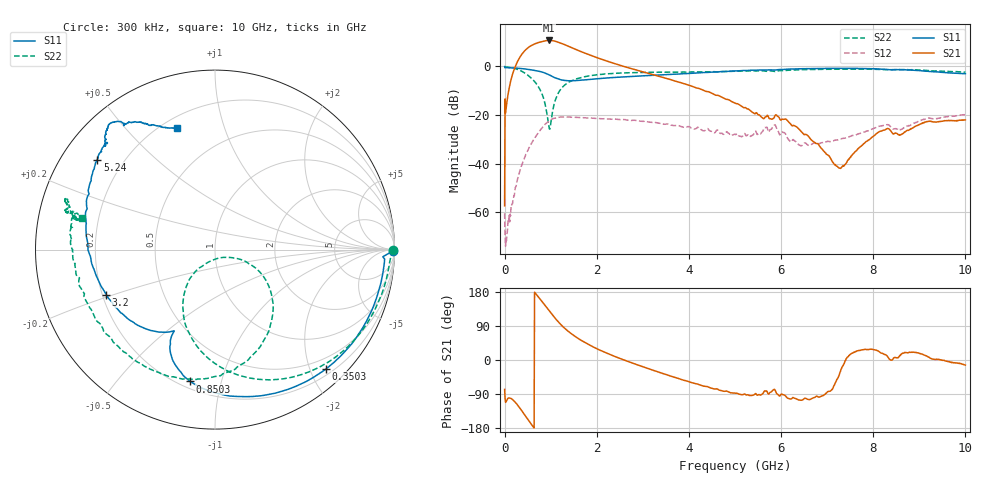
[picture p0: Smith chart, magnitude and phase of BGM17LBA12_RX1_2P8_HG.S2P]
!Agilent Technologies,E5071C,MY46316587,B.13.01
!Date: Fri Dec 08 10:52:52 2017
!Data & Calibration Information:
!Freq	S11:SOLT2(ON)	S21:SOLT2(ON)	S12:SOLT2(ON)	S22:SOLT2(ON)
!PortZ  Port1:50+j0  Port2:50+j0
!Above PortZ is port z conversion or system Z0 setting when saving the data.
!When reading, reference impedance value at option line is always used.
# Hz S dB R 50
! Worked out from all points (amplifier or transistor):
!   1001 points, 300 kHz to 10 GHz, reference 50 ohm
!   highest |S21| = 10.7 dB at 970.3 MHz (marker M1)
!   |S21| within 3 dB of that: 509.3 MHz to 1.459 GHz (950.1 MHz wide, 96.5 % of centre)
!   unconditionally stable (mu >= 1): start of sweep to end of sweep
!   at 1.66 GHz: K = 1.42, MAG = 9.7 dB, |S12| = -21.0 dB
!   at 5 GHz: K = 8.78, MAG = -6.0 dB, |S12| = -27.9 dB
!   at 10 GHz: K = 12.91, MAG = -15.2 dB, |S12| = -19.9 dB
!   lowest NFmin = 1.08 dB at 750 MHz
!   S11 on the Smith chart (normalised r, x): 300 kHz: open; 350.3 MHz: 0.30, -2.26; 850.3 MHz: 0.24, -0.80; 3.2 GHz: 0.22, -0.19; 5.24 GHz: 0.11, +0.34; 10 GHz: 0.26, +0.71
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300000  -0.06 -0.4  -57.37 -77.7  -60.44 90.1  -0.06 -0.2
6.02982e7  -0.50 -8.7  -13.28 -103.5  -67.89 118.9  -0.30 -11.4
2.102937e8  -0.63 -29.0  -1.13 -108.9  -53.25 155.8  -0.80 -37.9
3.502895e8  -0.84 -47.1  4.35 -130.0  -42.17 159.3  -1.77 -61.9
4.802856e8  -1.13 -62.7  7.23 -152.5  -35.50 148.9  -3.25 -82.9
6.202814e8  -1.54 -78.0  8.99 -176.3  -30.41 136.5  -5.59 -103.0
7.402778e8  -1.97 -90.1  9.87 165.1  -27.06 124.2  -8.58 -118.7
8.502745e8  -2.53 -100.6  10.42 148.8  -24.42 111.5  -13.36 -130.9
9.702709e8  -3.48 -110.0  10.69 129.8  -22.35 95.0  -25.65 -84.4
1.120266e9  -4.85 -115.8  10.25 106.8  -21.12 74.8  -12.89 -23.3
1.310261e9  -5.78 -116.6  8.90 83.1  -20.83 55.6  -7.58 -40.3
1.67025e9  -5.65 -118.7  6.02 51.3  -21.06 33.9  -4.51 -64.8
2.310231e9  -4.61 -131.7  1.64 13.3  -21.69 13.2  -2.94 -92.1
3.200204e9  -3.66 -157.5  -3.27 -26.1  -23.05 -6.9  -2.40 -120.5
3.3402e9  -3.51 -162.3  -3.99 -31.8  -23.33 -9.1  -2.38 -125.1
5.00015e9  -1.84 147.0  -15.06 -87.4  -27.91 -10.4  -2.02 -178.9
5.240143e9  -1.67 142.6  -17.12 -92.0  -28.52 -6.6  -1.89 175.4
5.850124e9  -1.47 135.2  -21.03 -77.5  -24.26 -9.3  -2.02 165.2
6.6701e9  -0.89 131.5  -30.47 -101.5  -31.94 10.6  -1.25 161.5
7.280082e9  -0.78 130.0  -41.86 -31.9  -29.98 30.4  -1.13 161.1
8.34005e9  -1.32 126.0  -25.67 3.9  -24.13 20.1  -1.38 163.5
1e10  -2.98 107.2  -22.01 -13.4  -19.85 4.5  -2.39 166.6
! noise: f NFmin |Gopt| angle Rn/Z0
6.5e+08  1.17  0.5022  67.04  0.3023
7e+08  1.123  0.5213  71.13  0.2529
7.5e+08  1.082  0.4911  70.9  0.231
8e+08  1.098  0.4998  75.77  0.2217
8.5e+08  1.129  0.4815  82.47  0.2049
9e+08  1.13  0.4811  82.36  0.214
9.5e+08  1.159  0.5074  85.01  0.2258
1e+09  1.175  0.4432  87.19  0.186
